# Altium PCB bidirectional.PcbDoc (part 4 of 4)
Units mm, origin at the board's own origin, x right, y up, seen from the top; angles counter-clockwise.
Board outline 190.5 x 127 mm, 6 copper layers (Top Layer, MidLayer1, MidLayer2, Mid-Layer 3, Mid-Layer 4, Bottom Layer), stack 2.997 mm thick; 416 components, 178 nets, 1084 pads, 2010 vias.

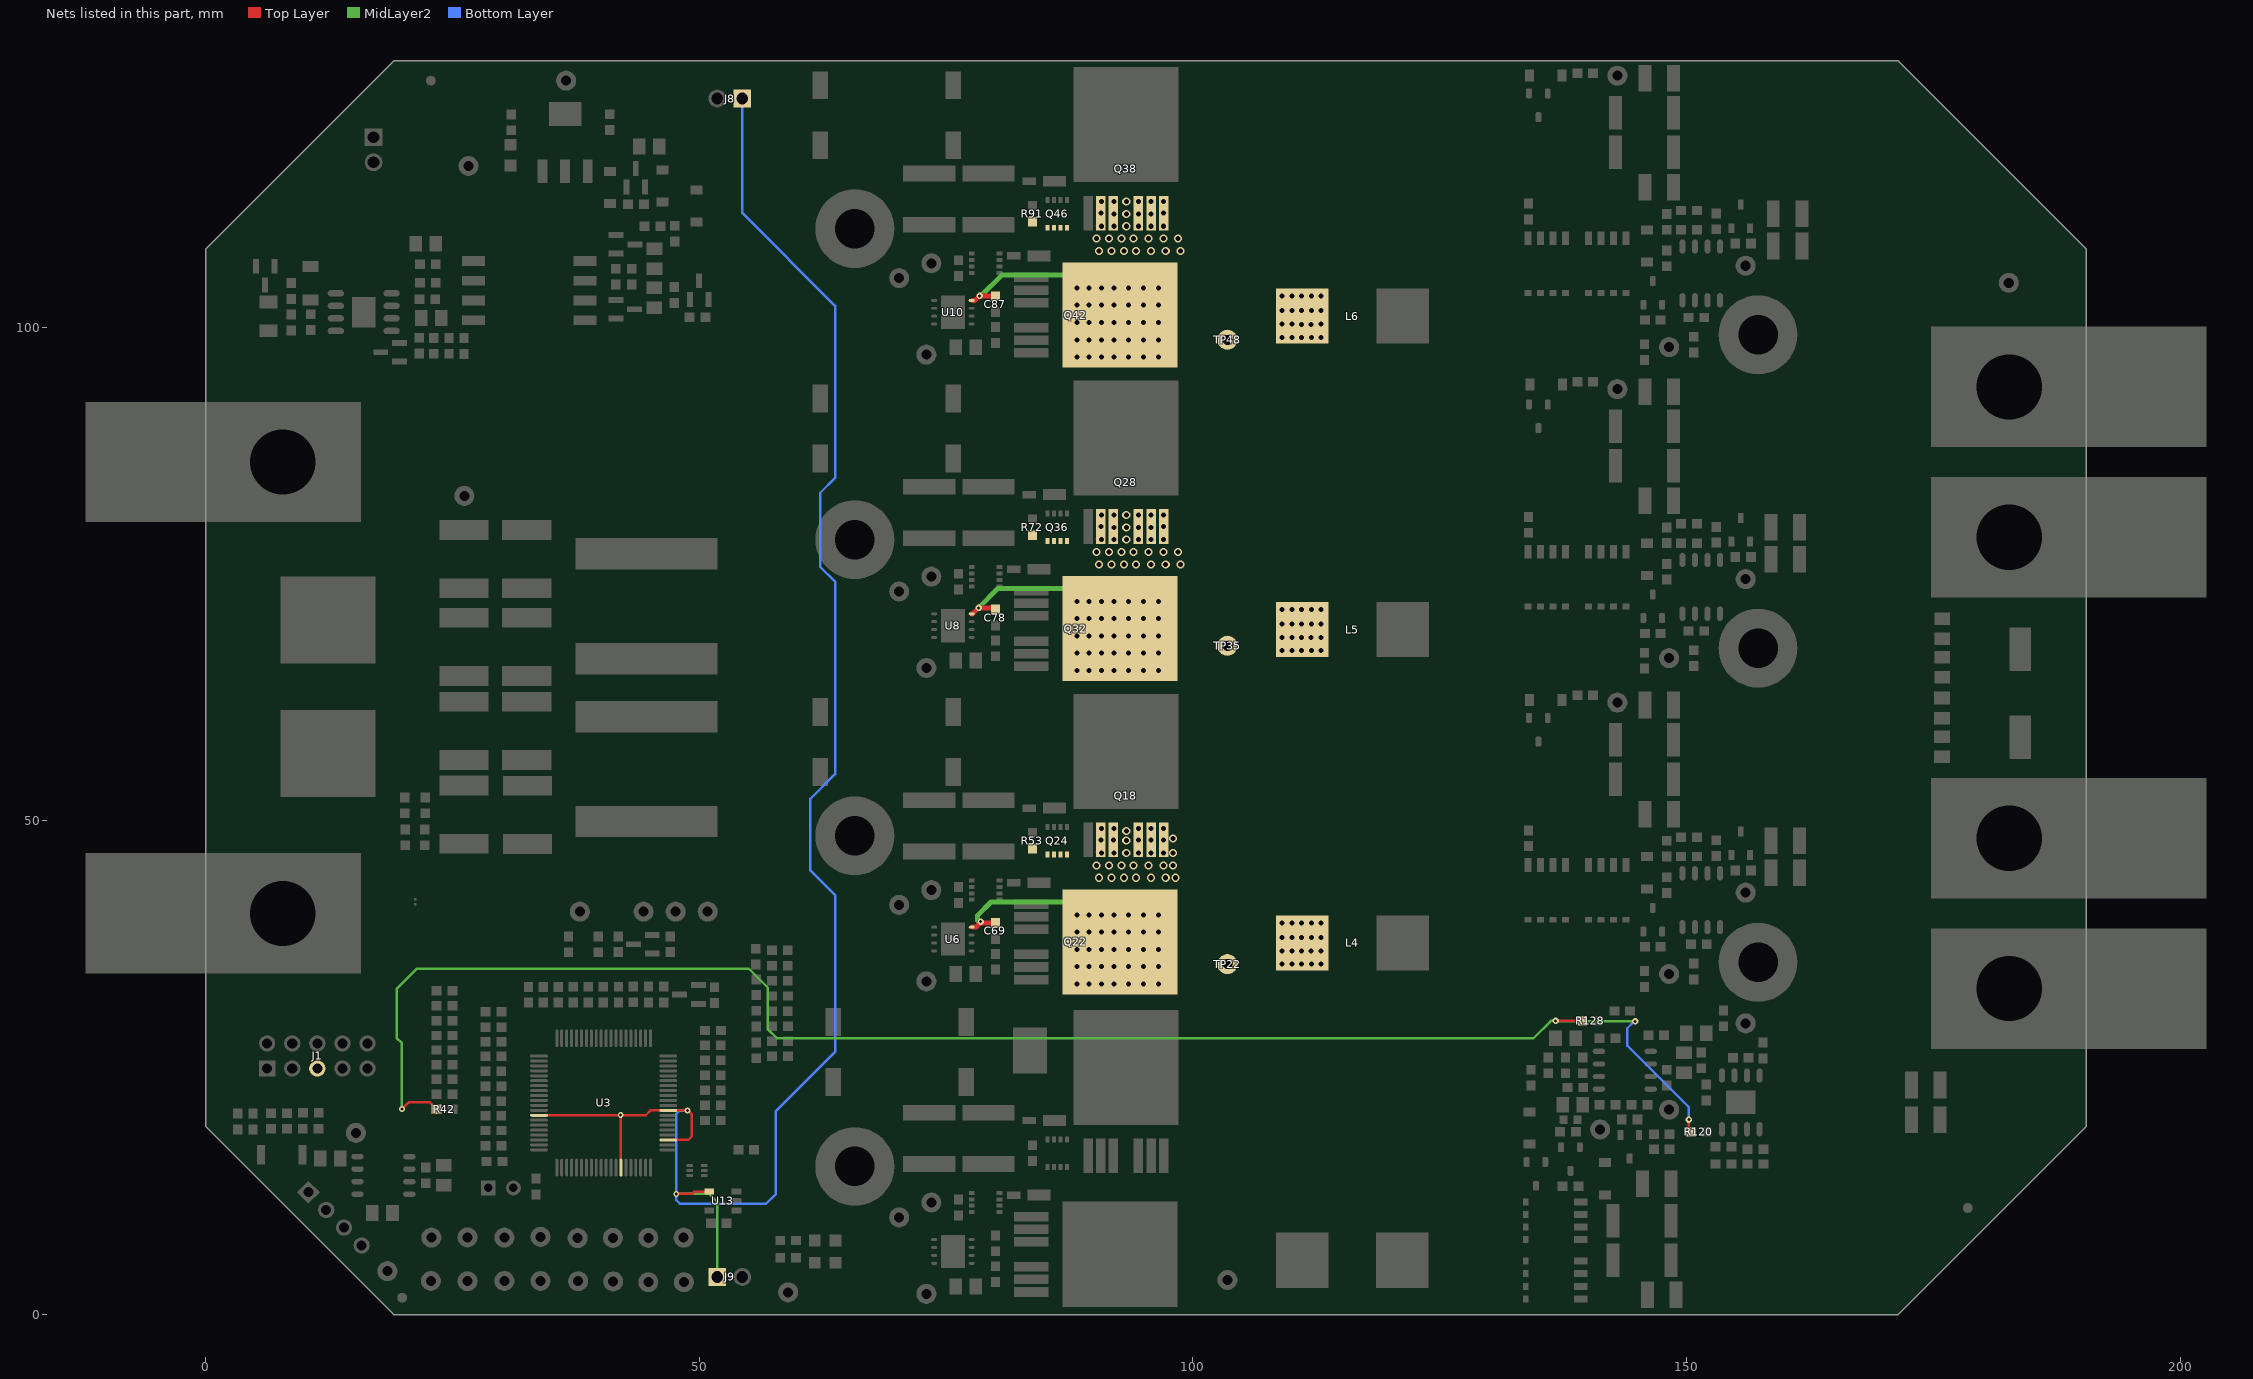
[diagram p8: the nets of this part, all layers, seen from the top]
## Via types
v1: diameter 0.813, hole 0.508, Top Layer to Bottom Layer, 1661 vias
v2: diameter 0.6, hole 0.3, Top Layer to Bottom Layer, 178 vias
v3: diameter 0.66, hole 0.3, Top Layer to Bottom Layer, 84 vias
v4: diameter 0.66, hole 0.3, Top Layer to Bottom Layer, tented both sides, 35 vias
v5: diameter 0.5, hole 0.2, Top Layer to Bottom Layer, 20 vias
v6: diameter 0.813, hole 0.508, Top Layer to Bottom Layer, tented both sides, 10 vias
v7: diameter 0.66, hole 0.33, Top Layer to Bottom Layer, tented top, 8 vias
v8: diameter 0.6, hole 0.3, Top Layer to Bottom Layer, tented both sides, 7 vias
v9: diameter 0.813, hole 0.508, Top Layer to Bottom Layer, tented top, 5 vias
v10: diameter 0.864, hole 0.406, Top Layer to Bottom Layer, 2 vias

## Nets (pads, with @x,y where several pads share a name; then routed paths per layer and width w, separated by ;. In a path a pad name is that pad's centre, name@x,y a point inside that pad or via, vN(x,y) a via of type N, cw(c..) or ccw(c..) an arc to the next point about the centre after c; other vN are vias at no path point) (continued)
SW2: C69.2 L4.1 Q18.2 Q18.3 Q18.5 Q18.6 Q18.7 Q22.4 Q24.5 Q24.6 Q24.7 Q24.8 R53.2 TP22.1 U6.4 | length 17.5
  Top Layer w0.254: Q18.2@90.274,46.822 Q18.2@90.373,46.723 ; L4.1@111.883,36.72 L4.1@112.849,35.754
  Top Layer w0.508: U6.4@77.686,39.243 78.019,39.243 78.438,39.662 C69.2@80,39.662 ; L4.1@110.993,37.609 L4.1@111.883,36.72 ; L4.1@111.049,35.763 L4.1@113.284,35.763 ; L4.1@112.849,35.754 L4.1@113,35.754
  MidLayer2 w0.508: v3@78.2,39.9 78.2,40.45 79.547,41.797 86.953,41.797
  other v1: 88.25,33.5 89.5,33.5 90.75,33.5 92,33.5 93.5,33.5 95,33.5 96.5,33.5 88.25,35.25 89.5,35.25 90.75,35.25 92,35.25 93.5,35.25 95,35.25 96.5,35.25 109.038,35.5 110.028,35.5 111.019,35.5 112.009,35.5 113,35.5 110.993,36.821 111.984,36.821 109.038,36.846 110.028,36.846 113,36.846 88.25,37 89.5,37 90.75,37 92,37 93.5,37 95,37 96.5,37 109.038,38.218 110.028,38.218 111.019,38.218 112.009,38.218 113,38.218 88.25,38.75 89.5,38.75 90.75,38.75 92,38.75 93.5,38.75 95,38.75 96.5,38.75 109.038,39.666 110.028,39.666 111.019,39.666 112.009,39.666 113,39.666 88.25,40.5 89.5,40.5 90.75,40.5 92,40.5 93.5,40.5 95,40.5 96.5,40.5 90.5,44.25 91.75,44.25 93,44.25 94.25,44.25 95.75,44.25 97.25,44.25 98.25,44.25 90.25,45.5 91.5,45.5 92.75,45.5 94,45.5 95.5,45.5 97,45.5 98,45.5 90.75,46.75 92,46.75 93.25,46.75 94.5,46.75 95.75,46.75 97,46.75 98,46.75 93.25,48 90.678,48.086 91.948,48.086 94.488,48.086 95.758,48.086 97.028,48.086 98,48.25 93.25,49 90.75,49.25 92,49.25 94.5,49.25 95.75,49.25 97,49.25
  other v3: 78.5,39.8
SW3: C78.2 L5.1 Q28.2 Q28.3 Q28.5 Q28.6 Q28.7 Q32.4 Q36.5 Q36.6 Q36.7 Q36.8 R72.2 TP35.1 U8.4 | length 19.2
  Top Layer w0.254: Q28.2@90.274,78.572 Q28.2@90.373,78.473 ; L5.1@111.883,68.47 L5.1@112.849,67.504
  Top Layer w0.508: U8.4@77.592,70.992 77.692,70.992 v3(78.3,71.6) 79.812,71.6 C78.2@80,71.412 ; L5.1@110.993,69.359 L5.1@111.883,68.47 ; L5.1@111.049,67.513 L5.1@113.284,67.513 ; L5.1@112.849,67.504 L5.1@113,67.504
  MidLayer2 w0.508: v3(78.3,71.6) 80.247,73.547 86.953,73.547 v1(88.25,72.25)
  other v1: 88.25,65.25 89.5,65.25 90.75,65.25 92,65.25 93.5,65.25 95,65.25 96.5,65.25 88.25,67 89.5,67 90.75,67 92,67 93.5,67 95,67 96.5,67 109.038,67.25 110.028,67.25 111.019,67.25 112.009,67.25 113,67.25 110.993,68.571 111.984,68.571 109.038,68.596 110.028,68.596 113,68.596 88.25,68.75 89.5,68.75 90.75,68.75 92,68.75 93.5,68.75 95,68.75 96.5,68.75 109.038,69.968 110.028,69.968 111.019,69.968 112.009,69.968 113,69.968 88.25,70.5 89.5,70.5 90.75,70.5 92,70.5 93.5,70.5 95,70.5 96.5,70.5 109.038,71.416 110.028,71.416 111.019,71.416 112.009,71.416 113,71.416 89.5,72.25 90.75,72.25 92,72.25 93.5,72.25 95,72.25 96.5,72.25 90.5,76 91.75,76 93,76 94.25,76 95.75,76 97.25,76 98.75,76 90.25,77.25 91.5,77.25 92.75,77.25 94,77.25 95.5,77.25 97,77.25 98.5,77.25 90.75,78.5 92,78.5 93.25,78.5 94.5,78.5 95.75,78.5 97,78.5 92,79.75 93.25,79.75 94.5,79.75 95.75,79.75 90.678,79.836 97.028,79.836 90.75,81 92,81 93.25,81 94.5,81 95.75,81 97,81
SW4: C87.2 L6.1 Q38.2 Q38.3 Q38.5 Q38.6 Q38.7 Q42.4 Q46.5 Q46.6 Q46.7 Q46.8 R91.2 TP48.1 U10.4 | length 18.9
  Top Layer w0.254: Q38.2@90.274,110.322 Q38.2@90.373,110.223 ; L6.1@111.883,100.22 L6.1@112.849,99.254
  Top Layer w0.508: U10.4@77.686,102.743 77.943,102.743 v3(78.4,103.2) 78.438,103.162 C87.2@80,103.162 ; L6.1@110.993,101.109 L6.1@111.883,100.22 ; L6.1@111.049,99.263 L6.1@113.284,99.263 ; L6.1@112.849,99.254 L6.1@113,99.254
  MidLayer2 w0.508: v3(78.4,103.2) 78.541,103.2 80.638,105.297 86.953,105.297 v1(88.25,104)
  other v1: 88.25,97 89.5,97 90.75,97 92,97 93.5,97 95,97 96.5,97 88.25,98.75 89.5,98.75 90.75,98.75 92,98.75 93.5,98.75 95,98.75 96.5,98.75 109.038,99 110.028,99 111.019,99 112.009,99 113,99 110.993,100.321 111.984,100.321 109.038,100.346 110.028,100.346 113,100.346 88.25,100.5 89.5,100.5 90.75,100.5 92,100.5 93.5,100.5 95,100.5 96.5,100.5 109.038,101.718 110.028,101.718 111.019,101.718 112.009,101.718 113,101.718 88.25,102.25 89.5,102.25 90.75,102.25 92,102.25 93.5,102.25 95,102.25 96.5,102.25 109.038,103.166 110.028,103.166 111.019,103.166 112.009,103.166 113,103.166 89.5,104 90.75,104 92,104 93.5,104 95,104 96.5,104 90.5,107.75 91.75,107.75 93,107.75 94.25,107.75 95.75,107.75 97.25,107.75 98.75,107.75 90.25,109 91.5,109 92.75,109 94,109 95.5,109 97,109 98.5,109 90.75,110.25 92,110.25 93.25,110.25 94.5,110.25 95.75,110.25 97,110.25 92,111.5 93.25,111.5 94.5,111.5 95.75,111.5 90.678,111.586 97.028,111.586 90.75,112.75 92,112.75 93.25,112.75 94.5,112.75 95.75,112.75 97,112.75
SYNC: J8.1 J9.1 U3.13 U3.34 U3.43 U3.49 U13.4 | length 182.8
  Top Layer w0.254: U3.13@33.76,20.188 v2@42.06,20.188 ; U3.34@42.06,14.888 v2@42.06,20.185 ; v2@42.062,20.188 44.572,20.188 45.072,20.688 U3.49@46.86,20.688 48.832,20.688 49.251,20.269 49.251,18.059 48.879,17.688 U3.43@46.86,17.688 ; v2(47.663,12.217) 49.263,12.217 49.502,12.456 U13.4@51,12.456
  MidLayer2 w0.254: v2(47.663,12.217) 51.003,12.217 51.816,11.405 J9.1@51.816,3.81
  Bottom Layer w0.254: v2(48.819,20.676) 48.006,20.676 47.676,20.345 47.676,12.23 v2(47.663,12.217) 47.663,11.595 48.031,11.227 56.75,11.227 57.747,12.224 57.747,20.607 63.75,26.61 63.75,42.5 61.25,45 61.25,52.25 63.75,54.75 63.75,74.25 62.25,75.75 62.25,83.25 63.75,84.75 63.75,102.19 54.356,111.584 J8.1@54.356,123.19
  other v2: 42.037,20.218
USB_V33: J1.5
ZCD: R42.1 R120.2 R128.1 | length 166.2
  Top Layer w0.254: v2(19.863,20.803) 20.586,21.526 22.657,21.526 R42.1@23.381,20.803 ; v3(136.75,29.75) R128.1@139.45,29.75 ; v3(150.25,19.75) 150.25,18.55 150.5,18.3 R120.2@150.45,18.25
  MidLayer2 w0.254: v2(19.863,20.803) 19.863,27.504 19.329,28.037 19.329,32.993 21.388,35.052 55.005,35.052 56.947,33.111 56.947,28.894 57.85,27.991 134.5,27.991 136.259,29.75 v3(136.75,29.75) 136.8,29.7 v3(144.8,29.7)
  Bottom Layer w0.254: v3(144.8,29.7) 144.7,29.7 144,29 144,27.25 150.25,21 v3(150.25,19.75)
pads on no net: C115.2 D1.2 D3.2 D4.2 FID1.1 FID2.1 FID3.1 H1.1 H2.1 H3.1 H4.1 H5.1 H6.1 H7.1 J1.3 J1.4 LBL1.0 T1.7 T1.8 U3.2 U3.11 U3.12 U3.14 U3.19 U3.20 U3.37 U3.38 U3.42 U3.45 U3.48 U3.50 U3.51 U3.52 U3.53 U3.55 U3.61 U3.62 U3.72 U3.73 U3.75 U7.1 U7.5 U7.8 U9.1 U9.5 U9.8 U11.1 U11.5 U11.8 U13.3 U15.3 U16.3 U17.3 U18.3
copper on no net: | length 0.7
  Bottom Layer w0.254: 51.562,19.736 52.045,19.253
  other v2: 18.999,21.946

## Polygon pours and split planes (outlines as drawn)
BAT_12V on Top Layer "MidLayer2-No Net 1" (solid, remove dead copper, pour order 31): 148,63 151,63 159.25,63 163,66.75 173.5,66.75 173.5,60 148,60
48V_CON on Top Layer "Bottom Layer-No Net" (solid, remove dead copper, pour order 42): 54.508,55.753 54.966,56.21 54.94,119.507 56.49,121.056 56.49,124.511 57.974,125.995 69.5,126.008 69.5,58.75 54.006,43.256 52.375,43.256 52.375,55.753
BAT_48V on Top Layer "Bottom Layer-No Net" (solid, remove dead copper, pour order 37): 16.332,65.913 14.58,65.913 3.505,65.913 3.124,66.294 3.124,72.873 3.124,92.1 3.454,92.431 3.48,92.456 13.056,92.456 52.527,92.456 52.959,92.024 52.959,90.043 52.959,75.997 52.426,75.463 52.4,75.438 51.079,75.438 37.49,75.438 36.728,76.2 34.696,78.232 33.579,78.232 22.022,78.232 21.438,77.648 21.438,74.981 21.438,66.421 20.93,65.913 16.332,65.913
PGND on Top Layer "Bottom Layer-No Net" (solid, remove dead copper, pour order 40): 18.186,53.823 23.139,58.776 35.357,58.75 35.992,59.385 35.992,66.472 35.458,67.005 24.054,67.005 21.641,64.592 3.658,64.592 3.099,64.033 3.099,35.027 3.581,34.544 17.704,34.544 18.186,35.027
48V_CON on Top Layer "Bottom Layer-No Net" (solid, pour order 38): 23.622,49.479 24.054,49.911 36.932,49.911 37.465,50.444 37.465,55.245 37.973,55.753 52.832,55.753 53.315,55.27 53.315,43.866 52.708,43.256 24.155,43.256 23.622,43.79
48V_CON on Top Layer "Bottom Layer-No Net" (solid, remove dead copper, pour order 43): 69.5,21.869 69.5,40.25 66.251,43.499 63.999,43.499 62.259,45.238 61.25,46.543 61.25,51 52.708,43.358 56.642,43.358 60.96,39.04 60.96,22.606 61.697,21.869
AGND on Top Layer "Bottom Layer-No Net" (solid, remove dead copper, pour order 45): 56.347,24 59.6,24 59.868,24.266 59.868,26.156 59.868,39.142 57.999,41 55.012,41 54.661,40.649 54.661,25.676
AGND on Top Layer "Bottom Layer-No Net" (solid, remove dead copper, pour order 46): 55.992,42.167 49.945,42.167 43.862,42.167 40.237,42.167 29.668,42.167 26.525,42.167 20.67,42.167 20.265,41.763 19.986,41.485 19.986,40.878 19.986,34.455 18.186,32.659 18.186,24.441 18.186,20.926 18.795,20.319 19.048,20.066 24.143,20.066 26.829,20.066 27.59,20.825 27.666,20.9 28.705,20.9 30.505,20.9 32.279,22.671 32.608,22.999 35.422,22.999 35.447,22.999 35.777,23.328 35.777,24.137 35.777,24.365 36.03,24.618 36.081,24.668 36.993,24.668 43.304,24.668 45.307,26.666 55.992,37.327 55.992,42.167
BAT_12V on Bottom Layer "Bottom Layer-No Net 4" (solid, remove dead copper, pour order 33): 148.25,90 148.25,123.5 149,124.25 151.25,124.25 153.5,126.5 171,126.5 189.75,107.75 189.75,90 149.5,90
AGND on Bottom Layer "Bottom Layer-No Net 3" (solid, remove dead copper, pour order 27): 8.9,11.4 16.4,3.9 18.7,3.9 19,3.9 20.3,5.2 20.3,7.5 23.2,10.4 23.2,16.9 22.6,17.5 12.7,17.5 11.4,16.2 8.9,13.7
BAT_12V on Bottom Layer "Bottom Layer-No Net 1" (solid, remove dead copper, pour order 34): 157.75,67 153.75,63 151.25,63 148.5,63 148,62.5 148,48 148.75,47.25 157,47.25 157.75,46.5 159.5,46.5 159.5,67
BAT_12V on Bottom Layer "Bottom Layer-No Net" (solid, remove dead copper, pour order 36): 148.25,15.25 148.25,0.75 170.5,0.75 189.75,20 189.75,95.25 165.71,95.25 165.21,94.75 148.25,94.75 148.25,80.838
PGND on Bottom Layer "Bottom Layer-No Net" (solid, remove dead copper, pour order 44): 99.893,30.893 104.381,30.893 131.857,30.893 132.75,30 132.75,13.75 131.884,12.884 126.326,12.884 115.366,12.884 112.75,15.5 102,15.5 99.643,17.857 99.643,30.643
AGND on Bottom Layer "Bottom Layer-No Net" (solid, remove dead copper, pour order 47): 18.186,20.93 18.186,47.727 19.05,48.59 19.126,48.666 29.007,48.666 59.03,48.666 60.096,47.6 60.122,47.574 60.122,44.806 60.122,24.968 59.309,24.155 59.258,24.105 56.845,24.105 55.601,24.105 54.458,25.248 54.051,25.654 43.129,25.654 35.204,25.654 34.569,25.019 34.417,24.867 34.417,23.52 34.417,20.98 33.553,20.117 28.956,20.117 18.999,20.117
NetD8_2 on Bottom Layer "MidLayer2-No Net" (solid, remove dead copper, pour order 50): 138.5,10 138.5,1.25 139,0.75 143.5,0.75 144,1.25 144,11.25 143.75,11.5 142.25,11.5 141.25,10.5 141,10.5 139,10.5
PGND on Bottom Layer "Bottom Layer-No Net 2" (solid, remove dead copper, pour order 28): 31.75,125.75 20.5,125.75 1.5,106.75 1.5,55 4.5,52 49.25,52 60.5,63.25 60.5,90.25 60.5,108.5 46.5,122.5 35,122.5 32.5,125
BAT_12V on MidLayer2 "MidLayer2-No Net 5" (solid, remove dead copper, pour order 30): 151.5,94.25 152.5,95.25 152.5,97.5 152.5,101.25 151.75,102 151.75,108.75 149.75,110.75 149.75,122.75 152.5,125.5 152.5,126.25 152.75,126.5 171,126.5 176.75,120.75 189.75,107.75 189.75,97.5 189.75,92.25 152.5,92.25 151.5,93.25
AGND on MidLayer2 "MidLayer2-No Net 4" (solid, remove dead copper, pour order 29): 8.75,11.75 8.75,13.5 12.75,17.5 20.5,17.5 21,17 21,8.25 20.25,7.5 17,4.25 16,4.25
BAT_12V on MidLayer2 "MidLayer2-No Net 2" (solid, remove dead copper, pour order 32): 152.5,63 152.75,63.25 152.75,78.75 150,81.5 150,94.75 189.75,94.75 189.75,61.75 152.5,61.75
SW1 on MidLayer2 "Bottom Layer-No Net" (solid, remove dead copper, pour order 39): 85.877,1.123 85.877,10.127 87.917,12.167 87.917,16.717 88.8,17.6 98.556,17.6 100.583,12.167 114.333,12.167 115.75,10.75 115.75,2 114.5,0.75 86.25,0.75
BAT_12V on MidLayer2 "Bottom Layer-No Net" (solid, remove dead copper, pour order 48): 148.25,1.25 148.25,15.5 148.75,16 151.25,16 151.25,62.941 173.75,62.941 175.006,62.916 175.031,62.941 189.75,62.941 189.75,20 170.5,0.75 148.75,0.75
NetD8_2 on MidLayer2 "MidLayer2-No Net" (solid, remove dead copper, pour order 49): 138.5,8.75 138.5,1.25 139,0.75 143.75,0.75 144,1 144,11 143.5,11.5 142.25,11.5 141.25,10.5 141,10.5 140.25,10.5
PGND on MidLayer2 "MidLayer2-No Net 3" (solid, remove dead copper, pour order 26): 37.318,126.25 19.5,126.25 0.75,107.5 0.75,50 1,49.75 37,49.75 37.75,50.5 37.75,125.207
PGND on MidLayer1 "Bottom Layer-No Net" (solid, remove dead copper, pour order 35): 0,107.95 19.05,127 171.45,127 190.5,107.95 190.5,19.05 171.45,0 19.05,0 0,19.05 0,107.95 0.025,107.975

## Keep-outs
Keep-Out Layer:
  the board outline again, w0.254

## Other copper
Top Layer:
  rectangle net NetC38_2: 23.673,69.596 28.651,74.651
  rectangle net NetC37_2: 30.023,69.596 35.001,74.574
  rectangle net NetC40_2: 23.647,52.603 28.677,57.201
  rectangle net NetC41_2: 29.997,52.578 35.103,57.201
  rectangle net NetL1_2: 37.49,58.953 51.867,68.072
  region net PHASE1: 72,31.35 70.75,30.1 70.75,18.85 71,18.6 82,18.6 82.25,18.85 82.25,20.6 82.75,21.1 87.5,21.1 89,19.6 98,19.6 98.5,20.1 98.5,30.85 98,31.35
  region net PGND: 85.5,1.004 85.5,8.754 85.25,9.004 82,9.004 81.154,9.85 80,9.85 79.75,10.1 79.75,11.1 79.25,11.6 78.25,12.6 77.75,12.6 77.25,12.1 77.25,10.85 76.75,10.6 75.75,10.6 75.75,9.6 79,9.6 79.5,9.1 80.5,9.1 81,8.6 81,1.004 81.25,0.754 85.25,0.754
  region net PGND: 70.548,15.85 70.548,14.302 71,13.85 81.5,13.85 81.798,14.148 81.798,15.6 81.548,15.85
  region net NetD13_1: 85,20.35 85,19.1 85.75,18.35 85.75,17.35 86.25,16.85 88.25,16.85 89.25,15.85 89.5,15.6 89.75,15.85 89.75,17.85 89.5,18.1 88.25,18.1 86,20.35
  region net PH1_H: 85.5,18.1 84.25,18.1 84,18.35 84,19.85 83,19.85 83,17.1 83.25,16.85 85.25,16.85 85.5,17.1
  region net SW1: 83.25,15.85 88,15.85 88.25,15.6 88.25,14.35 88.7,13.9 89.9,13.9 90.6,14.6 90.75,14.6 90.75,11.85 89.75,10.85 87.5,10.85 87,11.35 87,13.85 86.65,14.2 83.65,14.2 83.25,14.6
  region net NetD19_1: 80.25,11.85 80.25,10.35 80.5,10.1 81.5,10.1 82,9.6 85,9.6 85.25,9.85 85.25,12.6 85,12.85 83.75,12.85 83.5,12.6 83.5,11.335 83.25,11.085 81.265,11.085 80.5,11.85
  region net NetD21_1: 80.25,43.5 80.25,42 80.5,41.75 81.5,41.75 82,41.25 85,41.25 85.25,41.5 85.25,44.25 85,44.5 83.75,44.5 83.5,44.25 83.5,42.985 83.25,42.735 81.265,42.735 80.5,43.5
  region net SW2: 83.25,47.5 88,47.5 88.25,47.25 88.25,46.25 88.5,46 90,46 90.25,46.25 90.75,46.25 90.75,43.5 89.75,42.5 87.5,42.5 87,43 87,45.5 86.6,45.9 83.6,45.9 83.25,46.25
  region net PH2_H: 85.5,49.75 84.25,49.75 84,50 84,51.5 83,51.5 83,48.75 83.25,48.5 85.25,48.5 85.5,48.75
  region net NetD20_1: 85,52 85,50.75 85.75,50 85.75,49 86.25,48.5 88.25,48.5 89.25,47.5 89.5,47.25 89.75,47.5 89.75,49.5 89.5,49.75 88.25,49.75 86,52
  region net PGND: 70.548,47.5 70.548,45.952 71,45.5 81.5,45.5 81.798,45.798 81.798,47.25 81.548,47.5
  region net PGND: 85.5,32.654 85.5,40.404 85.25,40.654 82,40.654 81.154,41.5 80,41.5 79.75,41.75 79.75,42.75 79.25,43.25 78.25,44.25 77.75,44.25 77.25,43.75 77.25,42.5 76.75,42.25 75.75,42.25 75.75,41.25 79,41.25 79.5,40.75 80.5,40.75 81,40.25 81,32.654 81.25,32.404 85.25,32.404
  region net PHASE2: 72,63 70.75,61.75 70.75,50.5 71,50.25 82,50.25 82.25,50.5 82.25,52.25 82.75,52.75 87.5,52.75 89,51.25 98,51.25 98.5,51.75 98.5,62.5 98,63 84.7,63 82.375,62.125 80.2,63
  region net PHASE3: 72,94.75 70.75,93.5 70.75,82.25 71,82 82,82 82.25,82.25 82.25,84 82.75,84.5 87.5,84.5 89,83 98,83 98.5,83.5 98.5,94.25 98,94.75
  region net PGND: 85.5,64.404 85.5,72.154 85.25,72.404 82,72.404 81.154,73.25 80,73.25 79.75,73.5 79.75,74.5 79.25,75 78.25,76 77.75,76 77.25,75.5 77.25,74.25 76.75,74 75.75,74 75.75,73 79,73 79.5,72.5 80.5,72.5 81,72 81,64.404 81.25,64.154 85.25,64.154
  region net PGND: 70.548,79.25 70.548,77.702 71,77.25 81.5,77.25 81.798,77.548 81.798,79 81.548,79.25
  region net NetD22_1: 85,83.75 85,82.5 85.75,81.75 85.75,80.75 86.25,80.25 88.25,80.25 89.25,79.25 89.5,79 89.75,79.25 89.75,81.25 89.5,81.5 88.25,81.5 86,83.75
  region net PH3_H: 85.5,81.5 84.25,81.5 84,81.75 84,83.25 83,83.25 83,80.5 83.25,80.25 85.25,80.25 85.5,80.5
  region net SW3: 83.25,79.25 88,79.25 88.25,79 88.25,78 88.5,77.75 90,77.75 90.25,78 90.75,78 90.75,75.25 89.75,74.25 87.5,74.25 87,74.75 87,77.25 86.65,77.6 83.65,77.6 83.25,78
  region net NetD23_1: 80.25,75.25 80.25,73.75 80.5,73.5 81.5,73.5 82,73 85,73 85.25,73.25 85.25,76 85,76.25 83.75,76.25 83.5,76 83.5,74.735 83.25,74.485 81.265,74.485 80.5,75.25
  region net NetD25_1: 80.25,107 80.25,105.5 80.5,105.25 81.5,105.25 82,104.75 85,104.75 85.25,105 85.25,107.75 85,108 83.75,108 83.5,107.75 83.5,106.485 83.25,106.235 81.265,106.235 80.5,107
  region net SW4: 83.25,111 88,111 88.25,110.75 88.25,109.75 88.5,109.5 90,109.5 90.25,109.75 90.75,109.75 90.75,107 89.75,106 87.5,106 87,106.5 87,109 86.6,109.4 83.6,109.4 83.25,109.75
  region net PH4_H: 85.5,113.25 84.25,113.25 84,113.5 84,115 83,115 83,112.25 83.25,112 85.25,112 85.5,112.25
  region net NetD24_1: 85,115.5 85,114.25 85.75,113.5 85.75,112.5 86.25,112 88.25,112 89.25,111 89.5,110.75 89.75,111 89.75,113 89.5,113.25 88.25,113.25 86,115.5
  region net PGND: 159.25,112.75 156.5,112.75 156.25,112.5 156.25,108.25 157.5,107 159.25,107
  region net PGND: 160,81 156.5,81 156.25,80.75 156.25,76.5 157.5,75.25 160,75.25 160.25,75.5 160.25,80.75
  region net PGND: 159.25,49.25 157,49.25 156.25,48.5 156.25,44.75 157.5,43.5 159.25,43.5 159.75,44 159.75,48.75
  region net 3.3VD: 38.3,126.3 33.05,126.3 32.5,125.75 32.5,118 33,117.5 39.25,117.5 40,118.25 40,125.75 39.5,126.25
  region net PGND: 147,126.5 142.5,126.5 142,126 142,124.5 142.5,124 143.75,124 144.5,123.25 144.5,120.75 147,120.75
  region net PGND: 146.25,118.75 144.75,118.75 144.5,118.5 144.5,112.5 145,112 146.5,112 146.5,118.5
  region net NetL6_2: 118.5,97 119.6,95.9 143.65,95.9 144.5,96.75 144.5,106.75 144,107.25 119.5,107.25 118.5,106.25
  region net BAT_12V: 160.75,75 160.75,81.25 160.5,81.5 157,81.5 152.5,81.5 152,81 148.5,81 148.25,81.25 148.25,94.75 189.658,94.75 189.731,94.824 189.731,71.723 187.973,71.723 187.5,71.25 187.5,66.25 186.5,65.25 180.75,65.25 180,66 180,69.25 179.375,69.875 174.375,69.875 173.5,69 173.5,65.5 161.75,65.5 161.75,69.75 160.75,70.75
  region net NetL5_2: 118.5,65.25 119.75,64 143.5,64 144.5,65 144.5,75 144,75.5 119.5,75.5 118.5,74.5
  region net PGND: 146.5,87.5 144.5,87.5 144.5,81.5 144.75,81.25 146.5,81.25
  region net PGND: 147.5,94.75 142.5,94.75 142,94.25 142,92.75 142.5,92.25 143.75,92.25 144.5,91.5 144.5,88.5 147.5,88.5
  region net NetD12_2: 143.25,91.75 137.75,91.75 137,91 137,90 135,88 135,82 135,76.75 139.25,76.75 139.25,78.25 141,78.25 141,76.75 144.5,76.75 144.5,80 144,80.5 144,86.75 144,91
  region net SW3: 90.74,81.5 90.17,80.93 90.17,77.17 87.884,74.884 87.884,65.944 89.674,64.154 114.5,64.154 115.75,65.404 115.75,74.404 114.583,75.571 99.847,75.571 98.806,76.612 98.806,79.914 97.22,81.5
  region net PGND: 100,94 100,78.5 101.7,76.8 132,76.8 132.75,77.55 132.75,92.45 130.65,94.55 100.55,94.55
  region net BAT_12V: 148,63 148,49.75 148.5,49.25 154,49.25 154.5,49.75 159.25,49.75 159.25,63
  region net NetD10_2: 143.25,60 137.75,60 137,59.25 137,58.25 135,56.25 135,50.25 135,45.25 135.25,45 139.5,45 139.5,46.4 139.6,46.5 140.6,46.5 140.75,46.35 140.75,45 144.25,45 144.5,45.25 144.5,48.25 144,48.75 144,55 144,59.25
  region net PGND: 147.5,63 142.5,63 142,62.5 142,61 142.5,60.5 143.75,60.5 144.5,59.75 144.5,57 144.75,56.75 147.25,56.75 147.5,57
  region net PGND: 146.5,55.75 145,55.75 144.25,55 144.25,50 144.75,49.5 146.75,49.5 146.75,55.5
  region net NetL4_2: 118.5,33.5 119.75,32.25 143.75,32.25 144.5,33 144.5,43.25 144,43.75 119.5,43.75 118.5,42.75
  region net PGND: 100,62.25 100,46.5 101.45,45.05 132,45.05 132.5,45.55 132.5,62.55 132.25,62.8 100.55,62.8
  region net SW1: 90.424,17.78 90.17,17.526 90.17,13.37 87.884,11.084 87.884,2.54 89.674,0.75 114.5,0.75 115.75,2 115.75,11 114.75,12 100.014,12 98.806,13.208 98.806,16.51 97.536,17.78
  region net NetL3_2: 118.5,1.5 119.25,0.75 137.606,0.75 137.606,11.75 119,11.75 118.5,11.25
  region net NetD8_2: 138.6,10.5 141.25,10.5 142.25,11.5 143.5,11.5 144,11 144,1.25 143.5,0.75 138.75,0.75 138.5,1 138.5,4.25 138.75,4.5 141.5,4.5 141.75,4.75 141.75,6.25 141.5,6.5 139,6.5 138.5,7
  region net BAT_12V: 148,1.25 148.5,0.75 170.25,0.75 173.5,4 173.5,11 173.5,14 148,14
  region net BAT_12V: 157.75,13.5 158.75,14.5 158.75,29.75 161.75,32.75 161.75,38.75 160.125,40.375 160.125,48.875 159.25,49.75 158.75,63 173.5,63 173.5,11 172.5,10 157.75,10
  region net PGND: 100,30 100,14 101,13 131.75,13 132.25,13.5 132.25,30.25 131.75,30.75 100.75,30.75
  region net PGND: 147.5,7 144.5,7 144.5,1 144.75,0.75 147.5,0.75
  region net PGND: 146.25,14.5 144.25,14.5 143.75,14 143.75,12.75 144.5,11.25 144.5,8.25 144.75,8 146,8 146.25,8.25 146.25,11
  region net SW2: 90.424,49.434 90.17,49.18 90.17,45.42 87.884,43.134 87.884,34.194 89.674,32.404 114.5,32.404 115.75,33.654 115.75,42.654 114.583,43.821 99.847,43.821 98.806,44.862 98.806,48.164 97.536,49.434
  region net PGND: 174.75,55.25 174.75,17.5 175.75,16.5 186.75,16.5 189.75,19.5 189.75,54.25 187,54.25 186.5,54.75 186.5,60.25 186,60.75 181.25,60.75 180.75,60.25 180.75,55.75 180.25,55.25
  region net PGND: 100,126.3 100,110 101.45,108.55 132,108.55 132.75,109.3 132.75,124.35 130.8,126.3
  region net PGND: 70.548,111 70.548,109 70.798,108.75 81.548,108.75 81.798,109 81.798,110.75 81.548,111
  region net SW4: 90.424,112.934 90.17,112.68 90.17,108.92 87.884,106.634 87.884,97.694 89.674,95.904 114.5,95.904 115.75,97.154 115.75,106.154 114.583,107.321 99.847,107.321 98.806,108.362 98.806,111.664 97.536,112.934
  region net PGND: 85.5,96.154 85.5,103.904 85.25,104.154 82,104.154 81.154,105 80,105 79.75,105.25 79.75,106.25 79.25,106.75 78.25,107.75 77.75,107.75 77.25,107.25 77.25,106 76.75,105.75 75.75,105.75 75.75,104.75 79,104.75 79.5,104.25 80.5,104.25 81,103.75 81,96.154 81.25,95.904 85.25,95.904
  region net PHASE4: 72,126.5 70.75,125.25 70.75,114 71,113.75 82,113.75 82.25,114 82.25,115.75 82.75,116.25 87.5,116.25 89,114.75 98,114.75 98.5,115.25 98.5,126 98,126.5
  region net BAT_12V: 148.25,94.75 150.75,94.75 159.75,94.75 162,97 162,101.5 160.25,103.25 160.25,112.75 159.75,113.25 154.25,113.25 153.75,112.75 149.5,112.75 148.1,114.15 148.1,125.95 150,125 152,125 153.5,126.5 171,126.5 189.75,107.75 189.75,93.75 148.25,93.75
  region net NetD14_2: 143.25,123.5 137.75,123.5 137,122.75 137,121.75 135,119.75 135,113.75 135,108.5 139.25,108.5 139.25,110 141,110 141,108.5 144.5,108.5 144.5,111.75 144,112.25 144,118.5 144,122.75
  text ".Layer_Name" at -66,-4 h1.52
MidLayer1:
  region net PHASE3: 71.25,84.25 71.25,82.5 81.25,82.5 81.25,84.25
  region net PHASE4: 71.25,116 71.25,114.25 81.25,114.25 81.25,116
  region net SW4: 109.038,103.166 109.038,99 113,99 113,103.166
  region net SW3: 109.038,71.416 109.038,67.25 113,67.25 113,71.416
  region net PHASE4: 89.75,124 89,123.25 89,117.25 89.75,116.5 95.75,116.5 97,117.75 97,124
  region net SW4: 90.75,112.75 90.25,112.25 90.25,108 90.5,107.75 98.75,107.75 98.75,108.75 97,110.5 97,112.75
  region net SW4: 88.25,104 88.25,97 96.5,97 96.5,104
  region net PHASE3: 89,92.659 89,85.5 89.75,84.75 95.75,84.75 96.25,85.25 96.25,92.659
  region net SW3: 90.75,81 90.25,80.5 90.25,76.25 90.5,76 98.75,76 98.5,76.25 98.5,77.25 97,78.75 97,81
  region net SW3: 88.25,72.25 88.25,65.25 96.5,65.25 96.5,72.25
  pour cut-out: 59.5,0.25 59.5,38 60,38.5 60.75,38.5 61,38.25 61,-0.25 60.75,-0.5
  region net SW1: 95.44,10.3 89.5,10.3 89.5,2.7 96,2.7 96.4,3.1 96.4,9.34
  region net SW1: 93.25,17.25 90.75,17.25 90.3,16.8 90.3,13 97,13 98.5,14.5 98.5,16 97.3,17.2
  region net PHASE1: 77.5,18.3 85.1,18.3 88,20 97.75,20 97.75,21.5 79.9,21.5 77.4,19.7
  region net SW1: 109,7.9 113,7.9 113,2.9 109,2.9
  region net SW2: 88.25,40.5 88.25,33.5 96.75,33.5 96.75,40.25 96.5,40.5
  region net SW2: 90.75,49.25 90.25,48.75 90.25,44.5 90.5,44.25 98.75,44.25 98.75,47.5 97,49.25
  region net SW2: 109.038,39.666 109.038,35.5 113,35.5 113,39.666
  region net PHASE2: 89,60.75 89,53.75 89.75,53 95.75,53 96.25,53.5 96.25,60.909
  text ".Layer_Name" at -66,-7 h1.52
MidLayer2:
  region net PGND: 144.3,14.4 143.9,14 143.9,12.6 144.75,11.75 144.75,11 145,10.75 145.75,10.75 146,11 146,14.3 145.9,14.4
  region net 48V_CON: 61.4,32.25 60.5,33.15 60.5,41.5 59.5,42.5 54.75,42.5 54,43.25 54,55.016 54.737,55.753 62.247,55.753 63.25,54.75 63.25,47 67.5,42.75 67.5,38.75 69.5,36.75 69.5,32.5 69.25,32.25
  region net AGND: 21.4,20.9 21.4,16.8 18.6,14 17.2,14 16.5,14.7 16.5,15.4 20.4,19.3 20.4,20.8 20.7,21.1 21.3,21.1
  region net PGND: 81.25,16.35 81.71,15.89 81.71,13.81 81.271,13.371 70.979,13.371 70.5,13.85 70.5,15.6 71.25,16.35
  region net PHASE1: 70.75,21.7 70.75,18.85 71,18.6 98,18.6 98.75,19.35 98.75,21.7
  region net PHASE2: 71.7,62.7 70.75,61.75 70.75,50.5 71,50.25 98,50.25 98.75,51 98.75,62.7
  region net PGND: 81.25,48 81.71,47.54 81.71,45.46 81.271,45.021 70.979,45.021 70.5,45.5 70.5,47.25 71.25,48
  region net PGND: 81.25,79.75 81.71,79.29 81.71,77.21 81.271,76.771 70.979,76.771 70.5,77.25 70.5,79 71.25,79.75
  region net PGND: 85.75,72.25 85.25,72.75 81,72.75 80.5,72.25 80.5,64.25 80.55,64.2 85.7,64.2 85.75,64.25
  region net NetD14_2: 134.05,123.3 133.5,122.75 133.5,108.75 134,108.25 143.75,108.25 144.5,109 144.5,111.75 144,112.25 144,122.75 143.45,123.3
  region net NetL6_2: 118.5,96.75 119.5,95.75 142.5,95.75 143.75,97 143.75,102.5 144.5,103.25 144.5,106.75 144,107.25 119.5,107.25 118.5,106.25
  region net NetL5_2: 118.5,65 119.25,64.25 142.75,64.25 143.75,65.25 143.75,70.75 144.5,71.5 144.5,75 144,75.5 119.5,75.5 118.5,74.5
  region net NetD12_2: 134.25,91.75 133.5,91 133.5,77 134,76.5 143.75,76.5 144.5,77.25 144.5,80 144,80.5 144,91.25 143.5,91.75
  region net PGND: 100,93 99.5,92.5 99.5,77.25 100,76.75 132.5,76.75 133,77.25 133,92 132,93
  region net PHASE3: 72,94.75 70.75,93.5 70.75,82.25 71,82 98,82 98.75,82.75 98.75,94.25 98.25,94.75
  region net SW3: 86.25,64.5 86.5,64.25 114.5,64.25 116,65.75 116,74.25 114.75,75.5 99.5,75.5 98.75,76.25 98.75,80.25 97.5,81.5 88.25,81.5 87,80.25 87,75.25 86.75,75 86.25,74.5
  region net BAT_12V: 151.75,49.75 159.5,49.75 159.5,63 152.5,63 151.25,61.75 151.25,50.25
  region net NetD10_2: 134.25,60 133.5,59.25 133.5,45.25 134,44.75 143.75,44.75 144.5,45.5 144.5,48.25 144,48.75 144,59.5 143.5,60
  region net NetL4_2: 118.5,33.25 119.5,32.25 142.5,32.25 143.75,33.5 143.75,39 144.5,39.75 144.5,43.25 144,43.75 119.5,43.75 118.5,42.75
  region net NetL3_2: 118.5,1.5 119.25,0.75 137.25,0.75 137.75,1.25 137.75,11.25 136.75,12.25 119.5,12.25 118.5,11.25
  region net PGND: 85.25,9 84.95,9.3 81.05,9.3 80,8.25 80,1 80.25,0.75 85,0.75 85.25,1
  region net PGND: 85.75,40.5 85.25,41 81,41 80.5,40.5 80.5,32.5 80.75,32.25 85.5,32.25 85.75,32.5
  region net SW2: 86.25,32.75 86.75,32.25 114.25,32.25 116,34 116,42.5 114.75,43.75 99.5,43.75 98.75,44.5 98.75,48.75 98,49.5 88.75,49.5 87.25,48 87.25,43.75 86.75,43.25 86.25,42.75
  region net PGND: 100,61.25 99.5,60.75 99.5,45.5 100,45 132.5,45 133,45.5 133,60.25 132,61.25
  region net PGND: 85.75,104 85.25,104.5 81,104.5 80.5,104 80.5,96 80.75,95.75 85.5,95.75 85.75,96
  region net SW4: 86.25,96.25 86.75,95.75 114.25,95.75 116,97.5 116,106 114.75,107.25 99.5,107.25 98.75,108 98.75,112 97.5,113.25 88.25,113.25 87,112 87,107 86.75,106.75 86.25,106.25
  region net PHASE4: 70.75,121.5 70.75,114 71,113.75 98,113.75 98.75,114.5 98.75,124 98.5,124.25 88.5,124.25 87.25,123 72.25,123
  region net PGND: 99.5,124 99.5,109 100,108.5 132.5,108.5 133,109 133,123.75 132.5,124.25 99.75,124.25
  region net PGND: 81.25,111.5 81.71,111.04 81.71,108.96 81.271,108.521 70.979,108.521 70.5,109 70.5,110.75 71.25,111.5
  region net PGND: 101.25,21.25 100.75,20.75 100.75,14.25 101.75,13.25 131.75,13.25 132.75,14.25 132.75,20.25 131.75,21.25
  pour cut-out: 177,48.26 ccw(c182.702,48.26) 182.702,42.558 ccw(c182.702,48.26) 188.404,48.26 ccw(c182.702,48.26) 182.702,53.962 ccw(c182.702,48.26)
  pour cut-out: 177,33.02 ccw(c182.702,33.02) 182.702,27.318 ccw(c182.702,33.02) 188.404,33.02 ccw(c182.702,33.02) 182.702,38.722 ccw(c182.702,33.02)
  text ".Layer_Name" at -66,-10 h1.52
Mid-Layer 3:
  text ".Layer_Name" at -64.7,-27.3 h1.52
Mid-Layer 4:
  text ".Layer_Name" at -64.7,-27.3 h1.52
Bottom Layer:
  rectangle net NetL1_2: 37.363,58.928 51.892,68.097
  region net PGND: 70.75,16.1 70.5,15.85 70.5,14.35 71,13.85 81.5,13.85 81.75,14.1 81.75,15.85 81.5,16.1
  region net PHASE1: 72,31.35 70.75,30.1 70.75,19 98.5,19 98.5,30.6 97.75,31.35
  region net PHASE2: 70.75,61.55 70.75,50.5 71,50.25 98.25,50.25 98.5,50.5 98.5,62.25 97.75,63 84.883,63 83.5,62.1 71.3,62.1
  region net PGND: 70.75,47.75 70.5,47.5 70.5,46 71,45.5 81.5,45.5 81.75,45.75 81.75,47.5 81.5,47.75
  region net PGND: 70.75,79.5 70.5,79.25 70.5,77.75 71,77.25 81.5,77.25 81.75,77.5 81.75,79.25 81.5,79.5
  region net PGND: 70.75,111.25 70.5,111 70.5,109 70.75,108.75 81.25,108.75 81.75,109.25 81.75,110.75 81.25,111.25
  region net PGND: 81.25,73.5 80.5,72.75 80.5,64.5 80.9,64.1 85.6,64.1 85.75,64.25 85.75,73 85.25,73.5
  region net NetD14_2: 133.5,122.25 133.5,108.75 134,108.25 143.75,108.25 144.5,109 144.5,111.75 144,112.25 144,119.75 141,122.75 138.25,122.75 134,122.75
  region net NetL6_2: 118.5,106.25 118.5,96.75 119.5,95.75 143.5,95.75 144.75,97 144.75,106.5 144,107.25 119.5,107.25 118.75,106.5
  region net NetL5_2: 118.5,74.5 118.5,65 119.5,64 143.5,64 144.75,65.25 144.75,74.75 144,75.5 119.5,75.5 118.75,74.75
  region net NetD12_2: 134.25,91.75 133.5,91 133.5,77 134,76.5 143.75,76.5 144.5,77.25 144.5,80 144,80.5 144,91.25 143.5,91.75
  region net PGND: 81.25,41.75 80.5,41 80.5,32.75 80.85,32.4 85.65,32.4 85.75,32.5 85.75,41.25 85.25,41.75
  region net PGND: 100.25,94.5 99.75,94 99.75,80.25 100.7,79.3 113.2,79.3 115.5,77 131.75,77 133,78.25 133,93.5 132,94.5
  region net PHASE3: 72,94.75 70.75,93.5 70.75,82.25 71,82 98.25,82 98.5,82.25 98.5,94 97.75,94.75
  region net SW3: 112,78.263 100,78.263 98.5,79.763 98.5,81 98.25,81.25 89.25,81.25 88,81.25 87,80.25 87,76.013 87,64.5 87.225,64.275 114.762,64.275 115.75,65.263 115.75,74.513
  region net NetD10_2: 134.25,60 133.5,59.25 133.5,45.25 134,44.75 143.75,44.75 144.5,45.5 144.5,48.25 144,48.75 144,59.5 143.5,60
  region net NetL4_2: 118.5,42.75 118.5,33.25 119.5,32.25 143.75,32.25 144.75,33.25 144.75,43 144,43.75 119.5,43.75 118.75,43
  region net SW1: 98.25,17.75 92.25,17.75 87.5,17.75 87.5,13 87.5,0.762 114.762,0.762 115.75,1.75 115.75,11 112.25,14.5 101.5,14.5
  region net NetL3_2: 118.5,1.5 119.25,0.75 137.25,0.75 137.75,1.25 137.75,11.25 137.25,11.75 119,11.75 118.5,11.25
  region net PGND: 81.25,9.5 80.75,9 80.75,1.25 81.25,0.75 85,0.75 85.5,1.25 85.5,9.25 85.25,9.5
  region net SW2: 112.013,46.5 100.25,46.5 97,49.75 89,49.75 87.25,48 87.25,33 87.725,32.525 114.762,32.525 115.75,33.513 115.75,42.763
  region net PGND: 100.25,62.75 99.5,62 99.5,48.75 100.75,47.5 113.25,47.5 115.5,45.25 131.75,45.25 133,46.5 133,61.75 132,62.75
  region net SW4: 112,110.013 99.25,110.013 98.5,110.763 98.5,113 98.25,113.25 88.5,113.25 87,111.75 87,109.5 87,96.25 87.225,96.025 114.762,96.025 115.75,97.013 115.75,106.263
  region net PHASE4: 72,126.5 70.75,125.25 70.75,114 71,113.75 98.25,113.75 98.5,114 98.5,125.75 97.75,126.5
  region net PGND: 100.25,126.25 99.75,125.75 99.75,112 100.65,111.1 113.15,111.1 115.5,108.75 131.75,108.75 133,110 133,125.25 132,126.25
  region net PGND: 81.25,105.25 80.5,104.5 80.5,96.25 81,95.75 85.5,95.75 85.75,96 85.75,104.75 85.25,105.25
  pour cut-out: 177,48.26 ccw(c182.702,48.26) 182.702,42.558 ccw(c182.702,48.26) 188.404,48.26 ccw(c182.702,48.26) 182.702,53.962 ccw(c182.702,48.26)
  pour cut-out: 177,33.02 ccw(c182.702,33.02) 182.702,27.318 ccw(c182.702,33.02) 188.404,33.02 ccw(c182.702,33.02) 182.702,38.722 ccw(c182.702,33.02)
  text ".Layer_Name" at -66,-13 h1.52

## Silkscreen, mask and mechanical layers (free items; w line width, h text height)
Top Overlay:
  lines w0.254: 28.448,97.638 37.059,97.638 ; 28.448,109.931 37.363,109.931 ; 132.8,71.65 132.8,94.256 ; 132.8,71.65 132.8,94.256 ; 132.8,71.65 99.272,71.65 99.272,94.256 132.8,94.256 ; 132.8,103.4 132.8,126.006 ; 132.8,103.4 132.8,126.006 ; 132.8,103.4 99.272,103.4 99.272,126.006 132.8,126.006 ; 132.8,103.4 132.8,126.006 ; 99.25,7.75 99.25,30.5 132.778,30.5 132.778,7.75 99.25,7.75 ; 99.272,39.9 132.8,39.9 132.8,62.506 99.272,62.506 99.272,39.9
  text "3V3" at 38.8,125 h2
  text "PGND" at 23.4,112.9 h2
  text "PH4l" at 70.4,107.85 h1
  text "PH4H" at 68.6,102.65 h1
  text "SAFTY_SW4" at 139.5,96.7 h1
  text "SW4" at 104.9,96.5 h2
  text "PGND" at 69.9,94.2 h2
  text "+" at 169.1,89.5 h10
  text "48V" at 23.7,86.3 h2
  text "+" at 17.2,85.8 h10
  text "12V" at 166.8,84.6 h5
  text "Bidirectional DC-DC" at 35.4,84.4 h2
  text "REV 2.0" at 35.3,82.8 h1.5
  text "PH3l" at 72,76.5 h1
  text "48V" at 3.1,76.1 h5
  text "+" at 169,75.1 h10
  text "PH3H" at 68.6,70.9 h1
  text "SAFTY_SW3" at 139.35,65.3 h1
  text "SW3" at 103.8,64.9 h2
  text "PGND" at 70.2,62.3 h2
  text "GND" at 1.6,47.6 h5
  text "-" at 168.7,45.5 h10
  text "ISENSE" at 44.9,45.2 h2
  text "PH2l" at 72.6,44.8 h1
  text "12VSEN" at 38.6,43.7 h2
  text "48VSEN" at 30.5,42.3 h2
  text "AGND" at 52.702,41.262 h2
  text "PH2H" at 68.6,39.15 h1
  text "GND" at 163.4,39.1 h5
  text "-" at 16.7,38.2 h10
  text "SAFTY_SW2" at 141.2,35.8 h1
  text "SW2" at 104.7,33.1 h2
  text "-" at 168.7,31.7 h10
  text "PGND" at 70.9,30.8 h2
  text "PH1" at 82.2,22.5 h2
  text "CANRX" at 17,18.4 h2
  text "PH1l" at 70.4,12.7 h1
  text "BUCK" at 60.4,8.8 h3
  text "PH1H" at 68.6,7.5 h1
  text "CANTX" at 17.1,5.8 h1.5
  text ".Layer_Name" at -66,2 h1.52
  text "BOOST" at 61,1.8 h3
  text "SW1" at 104.7,0.9 h2
  text "PGND" at 60.5,0.2 h2
  text "PGND" at 67,0.2 h2
Bottom Overlay:
  text ".Layer_Name" at -66,-19 h1.52
Top Paste:
  text ".Layer_Name" at -66,5 h1.52
  text ".Layer_Name" at -63.703,-67.399 h0.76
Bottom Paste:
  text ".Layer_Name" at -66,-22 h1.52
  text ".Layer_Name" at -63.703,-67.399 h0.76
Top Solder:
  text ".Layer_Name" at -66,-1 h1.52
  text ".Layer_Name" at -63.703,-67.399 h0.76
  text ".Layer_Name" at -63.703,-67.399 h0.76
Bottom Solder:
  text ".Layer_Name" at -66,-16 h1.52
  text ".Layer_Name" at -63.703,-67.399 h0.76
M1 Board Outline:
  the board outline again, w0.2
  text ".Layer_Name" at -66,11 h1.52
  text ".Layer_Name" at -63.703,-67.399 h0.76
M2 Board Dimensions:
  text ".Layer_Name" at -66,8 h1.52
  text ".Layer_Name" at -63.703,-67.399 h0.76
M3 3D STEP Top:
  text ".Layer_Name" at -63.703,-67.399 h0.76
M4 3D STEP Bottom:
  text ".Layer_Name" at -63.703,-67.399 h0.76
M5 Assembly Top:
  lines w0.254: -85.268,-68.711 82.372,-68.711 ; -85.268,-63.547 82.423,-63.547 ; -85.268,-58.382 -85.268,-73.876 16.459,-73.876 82.423,-73.876 82.423,-58.382 -85.255,-58.382 -85.255,-73.876 -45.237,-73.876 ; -22.657,-73.876 -22.657,-58.382 ; 9.525,-63.547 9.525,-58.382 ; 30.861,-63.547 30.861,-58.382 ; 46.66,-74.041 46.66,-68.889
  text "PCB VIEWED FROM TOP SIDE" at -84.163,-62.247 h0.76
  text "BOARD #:" at -21.26,-62.247 h0.76
  text ".PRJ_Number" at -7.404,-62.247 h0.76
  text "REV:" at 14.046,-62.247 h0.76
  text ".PCB_Rev" at 21.45,-62.247 h0.76
  text "SVN REV:" at 35.331,-62.247 h0.76
  text ".VersionControl_RevNumber" at 48.184,-62.247 h1.2
  text "IGNORE ->" at -84.163,-67.399 h0.76
  text "PLOT NAME =" at -84.163,-72.627 h0.76
  text ".plot_File_Name" at -63.703,-72.627 h0.76
  text "GENERATED    :" at -21.209,-72.627 h0.76
  text ".Print_Date" at 0.876,-72.627 h0.76
  text ".Print_Time" at 19.393,-72.627 h0.76
  text "TEXAS INSTRUMENTS" at 51.511,-72.627 h0.76
M6 Assembly Bottom:
  lines w0.254: -85.281,-63.559 82.41,-63.559 ; -85.23,-68.724 82.41,-68.724 ; -49.517,-74.054 -49.517,-68.902 ; -33.718,-63.559 -33.718,-58.395 ; -12.383,-63.559 -12.383,-58.395 ; 0,63.5 190.5,63.5 ; 0,95.25 190.5,95.25 ; 2.5,31.7 190.5,31.75 ; 19.799,-73.889 19.799,-58.395 ; 42.38,-73.889 82.398,-73.889 82.398,-58.395 -85.281,-58.395 -85.281,-73.889 -19.317,-73.889 82.41,-73.889 82.41,-58.395 ; 165.1,86.36 190.5,86.36
  text ".VersionControl_RevNumber" at -52.057,-62.26 h0.76
  text "SVN REV:" at -39.205,-62.26 h0.76
  text ".PCB_Rev" at -25.324,-62.26 h0.76
  text "REV:" at -17.92,-62.26 h0.76
  text ".PRJ_Number" at 3.531,-62.26 h0.76
  text "BOARD #:" at 17.386,-62.26 h0.76
  text "PCB VIEWED FROM BOTTOM SIDE" at 80.289,-62.26 h0.76
  text "IGNORE ->" at -13.644,-67.399 h0.76
  text "TEXAS INSTRUMENTS" at -55.385,-72.64 h0.76
  text ".Print_Time" at -23.266,-72.64 h0.76
  text ".Print_Date" at -4.75,-72.64 h0.76
  text "GENERATED    :" at 17.335,-72.64 h0.76
  text ".plot_File_Name" at 59.83,-72.64 h0.76
  text "PLOT NAME =" at 80.289,-72.64 h0.76
M9 Title Sheet:
  drawing of 57 lines, arcs and shapes, not listed
  text "1" at -59.567,158.534 h0.76
  text "2" at 3.823,158.534 h0.76
  text "3" at 67.052,158.534 h0.76
  text "4" at 130.721,158.534 h0.76
  text "5" at 194.196,158.534 h0.76
  text "6" at 257.823,158.534 h0.76
  text "A" at -88.938,129.502 h0.76
  text "A" at 286.982,129.502 h0.76
  text "B" at -88.938,69.05 h0.76
  text "B" at 286.982,69.05 h0.76
  text "C" at -88.938,8.725 h0.76
  text "C" at 286.982,8.725 h0.76
  text "PROJECT TITLE:" at 209.766,-38.544 h0.76
  text ".PRJ_Title" at 211.036,-41.931 h0.76
  text "DESIGNED FOR:" at 209.766,-46.19 h0.76
  text ".PRJ_Customer" at 211.036,-49.746 h0.76
  text "D" at -88.938,-51.473 h0.76
  text "D" at 286.982,-51.473 h0.76
  text "FILE NAME:" at 209.766,-53.81 h0.76
  text ".PCB_File_Name_No_Path" at 211.036,-56.858 h0.76
  text "Texas Instruments (TI) and/or its licensors do not warrant the accuracy or completeness of this specification" at 83.541,-60.969 h0.76
  text "ENGINEER:" at 209.766,-61.176 h0.76
  text "LAYOUT BY:" at 247.993,-61.176 h0.76
  text "or any information contained therein. TI and/or its licensors do not warrant that this design will meet" at 82.398,-63.83 h0.76
  text ".PRJ_Engineer" at 211.036,-65.113 h0.76
  text ".PCB_Layout" at 249.276,-65.113 h0.76
  text "the specifications, will be suitable for your application or fit for any particular purpose, or will operate in" at 82.398,-66.692 h0.76
  text ".Layer_Name" at -63.703,-67.399 h0.76
  text "ALTIUM DESIGNER VERSION:" at 247.993,-69.05 h0.76
  text "an implementation. TI and/or its licensors do not warrant that the design is production worthy. You should" at 82.398,-69.554 h0.76
  text "completely validate and test your design implementation to confirm the system functionality for your application." at 83.541,-72.415 h0.76
  text ".print_Scale" at 211.036,-72.436 h0.76
  text ".Application_BuildNumber" at 249.276,-72.436 h0.76
  text "1" at -59.567,-77.686 h0.76
  text "2" at 3.823,-77.686 h0.76
  text "3" at 67.052,-77.686 h0.76
  text "4" at 130.721,-77.686 h0.76
  text "5" at 194.196,-77.686 h0.76
  text "6" at 257.823,-77.686 h0.76
M10 Fab Notes:
  text ".Layer_Name" at -63.703,-67.399 h0.76
M11 Gerber Information:
  lines w0.254: -85.268,-68.711 82.372,-68.711 ; -85.268,-63.547 82.423,-63.547 ; -85.268,-58.382 -85.268,-73.876 16.459,-73.876 82.423,-73.876 82.423,-58.382 -85.255,-58.382 -85.255,-73.876 -45.237,-73.876 ; -22.657,-73.876 -22.657,-58.382 ; 9.525,-63.547 9.525,-58.382 ; 30.861,-63.547 30.861,-58.382 ; 46.66,-74.041 46.66,-68.889
  text "ALL ARTWORK VIEWED FROM TOP SIDE" at -84.163,-62.247 h0.76
  text "BOARD #:" at -21.26,-62.247 h0.76
  text ".PRJ_Number" at -7.404,-62.247 h0.76
  text "REV:" at 14.046,-62.247 h0.76
  text ".PCB_Rev" at 21.45,-62.247 h0.76
  text "SVN REV:" at 35.331,-62.247 h0.76
  text ".VersionControl_RevNumber" at 48.184,-62.247 h0.76
  text "LAYER NAME =" at -84.163,-67.399 h0.76
  text "PLOT NAME =" at -84.163,-72.627 h0.76
  text ".plot_File_Name" at -63.703,-72.627 h0.76
  text "GENERATED    :" at -21.209,-72.627 h0.76
  text ".Print_Date" at 0.876,-72.627 h0.76
  text ".Print_Time" at 19.393,-72.627 h0.76
  text "TEXAS INSTRUMENTS" at 51.511,-72.627 h0.76
M12 Stackup:
  text ".Layer_Name" at -63.703,-67.399 h0.76
M13 Component Bodies Top:
  text ".Layer_Name" at -63.703,-67.399 h0.76
M14 Component Bodies Bottom:
  text ".Layer_Name" at -63.703,-67.399 h0.76
M15 Courtyards Top:
  text ".Layer_Name" at -63.703,-67.399 h0.76
M16 Courtyards Bottom:
  text ".Layer_Name" at -63.703,-67.399 h0.76

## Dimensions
0,107.95 to 190.5,107.95 on M2 Board Dimensions
171.45,127 to 171.45,0 on M2 Board Dimensions
0,19.05 to 19.05,0 on M2 Board Dimensions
